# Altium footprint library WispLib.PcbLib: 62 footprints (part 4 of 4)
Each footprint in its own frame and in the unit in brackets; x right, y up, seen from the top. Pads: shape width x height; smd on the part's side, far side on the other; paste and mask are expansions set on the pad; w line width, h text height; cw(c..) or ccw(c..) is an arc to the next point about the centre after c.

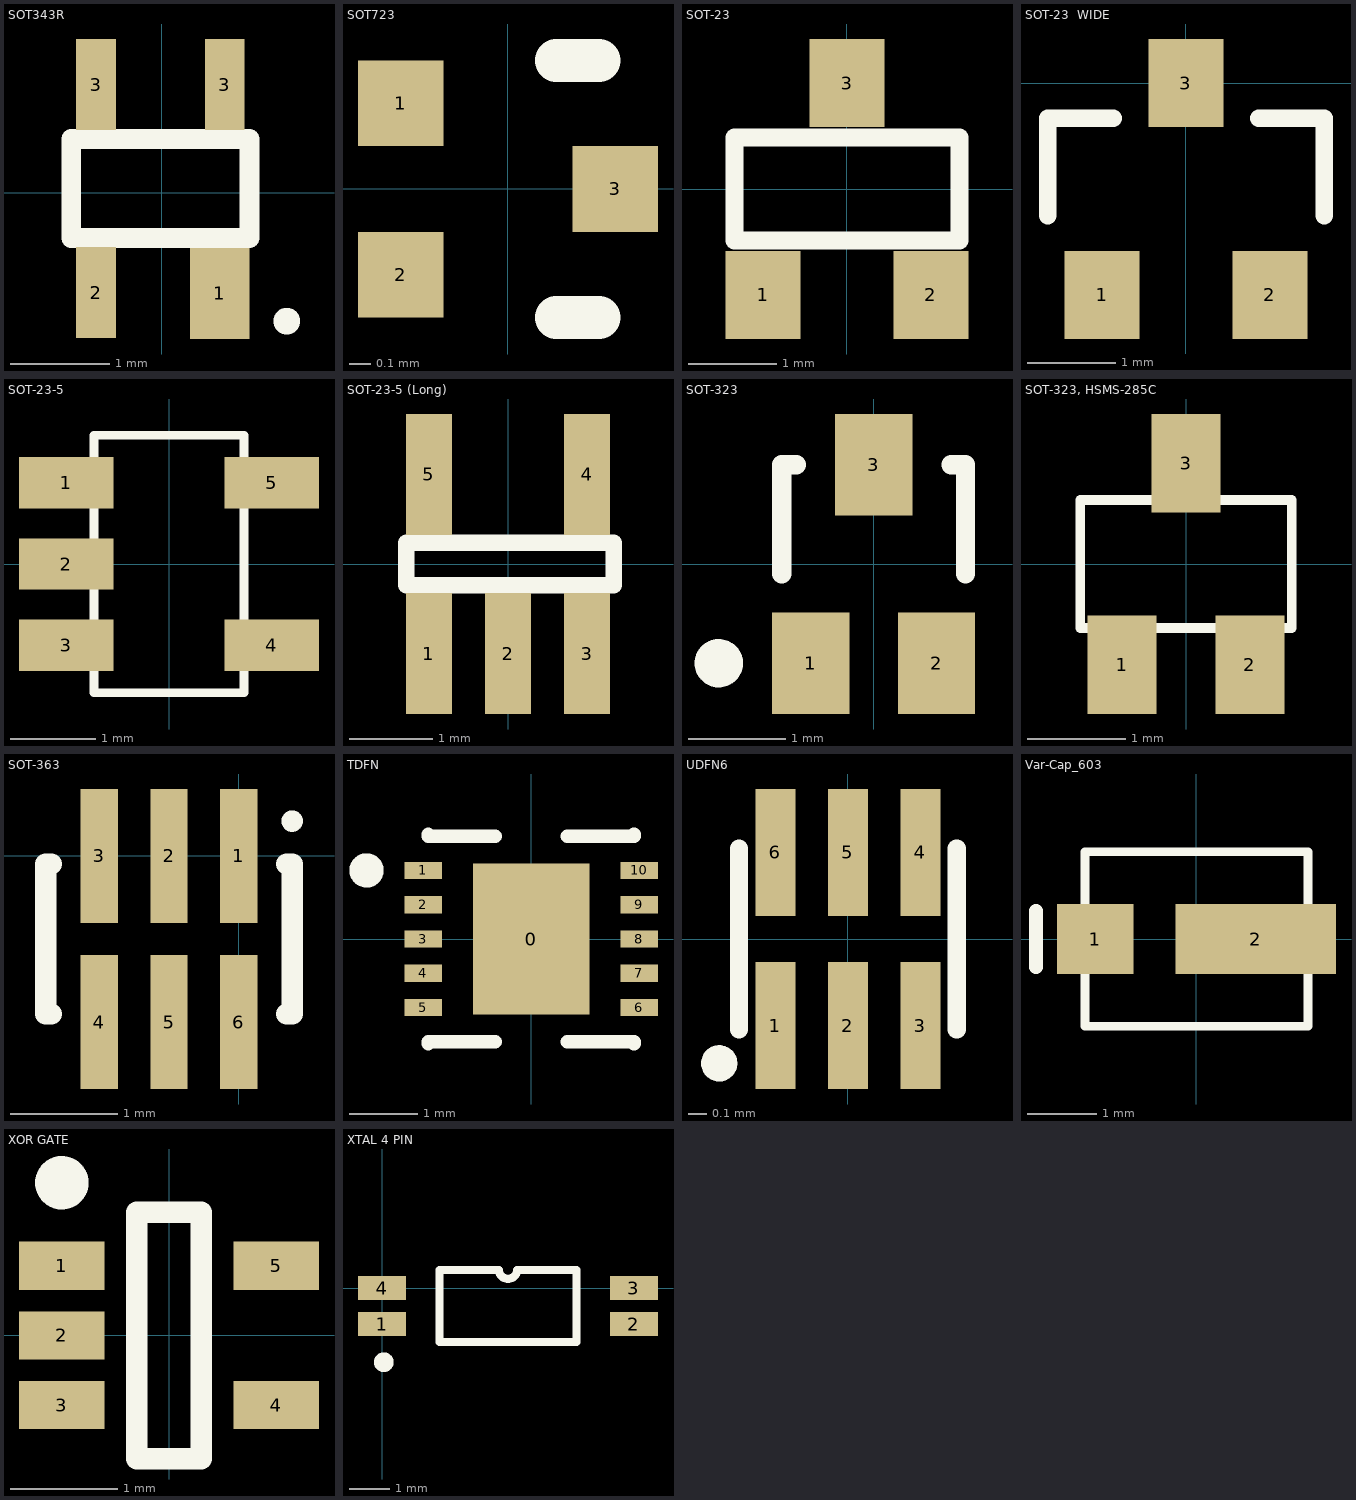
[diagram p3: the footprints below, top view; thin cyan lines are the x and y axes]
## SOT343R [mm] "SOT343R Package for BF1212"
pads (4):
  rect 0.6x0.92 smd: 1(0.584,-1.016)
  rect 0.4x0.92 smd: 2(-0.664,-1.007) 3(-0.664,1.093) 3(0.636,1.093)
Top Overlay:
  circle w0.254: c1.262,-1.295 r0.008
  lines w0.2: -0.914,-0.457 0.886,-0.457 0.886,0.543 -0.914,0.543 -0.914,-0.457

## SOT723 [mm] "SOT723, 3-Leads, Body 1.3x1.3mm (max), Pitch 0.40mm, IPC Medium Density"
height 0.55
pads (3):
  rect 0.4x0.4 smd: 1(-0.5,0.4) 2(-0.5,-0.4) 3(0.5,0)
Top Overlay:
  lines w0.2: 0.225,-0.6 0.425,-0.6 ; 0.225,0.6 0.425,0.6

## SOT-23 [mm] "SOT-23; 3 Leads; Body 3.0 x 2.5 mm, inc. leads (LxW max)"
pads (3):
  rect 0.85x1 smd: 1(-0.95,-1.2) 2(0.95,-1.2) 3(0,1.2)
Top Overlay:
  lines w0.2: -1.275,-0.584 -1.275,0.584 1.275,0.584 1.275,-0.584 -1.275,-0.584

## SOT-23  WIDE [mm] "SOT-23  WIDE"
height 0.127
pads (3):
  rect 0.85x1 smd: 1(-0.95,-2.4) 2(0.95,-2.4) 3(0,0)
Top Overlay:
  lines w0.2: -1.565,-1.5 -1.565,-0.4 -0.825,-0.4 ; 0.825,-0.4 1.565,-0.4 1.565,-1.5

## SOT-23-5 [mm] "SOT23, 5-Leads, Body 3.0x3.0mm (max), Pitch 0.95mm, IPC Medium Density"
height 1.45
pads (5):
  rect 1.1x0.6 smd: 1(-1.2,0.95) 2(-1.2,0) 3(-1.2,-0.95) 4(1.2,-0.95) 5(1.2,0.95)
Top Overlay:
  lines w0.1: -0.875,-1.5 -0.875,1.5 0.875,1.5 0.875,-1.5 -0.875,-1.5

## SOT-23-5 (Long) [mm] "SOT-23/SC-74A; 5 Leads; Body 3 x 3.1 mm, inc. leads (LxW max)"
height 1.45
pads (5):
  rect 0.55x1.45 smd: 1(-0.95,-1.075) 2(0,-1.075) 3(0.95,-1.075) 4(0.95,1.075) 5(-0.95,1.075)
Top Overlay:
  lines w0.2: -1.219,-0.254 -1.219,0.254 1.27,0.254 1.27,-0.254 -1.219,-0.254

## SOT-323 [mm] "SOT-323/SC-70; 3 Leads; Body 2.2 x 2.2 mm, inc. leads (LxW max)"
height 1
pads (3):
  rect 0.8x1.05 smd: 1(-0.65,-1.025) 2(0.65,-1.025) 3(0,1.025)
Top Overlay:
  circle w0.25: c-1.6,-1.025 r0.125
  lines w0.2: -0.95,-0.1 -0.95,1.025 -0.8,1.025 ; 0.8,1.025 0.95,1.025 0.95,-0.1

## SOT-323, HSMS-285C [mm] "SOT-323/SC-70; 3 Leads; HSMS-285C"
height 1
pads (3):
  rect 0.7x1 smd: 1(-0.65,-1.025) 2(0.65,-1.025) 3(0,1.025)
Top Overlay:
  lines w0.1: -1.075,-0.65 1.075,-0.65 1.075,0.65 -1.075,0.65 -1.075,-0.65

## SOT-363 [mm] "SOT-363 ,SC-88 ,6 Lead"
pads (6):
  rect 0.35x1.25 smd: 1(0,0) 2(-0.65,0) 3(-1.3,0) 4(-1.3,-1.55) 5(-0.65,-1.55) 6(0,-1.55)
Top Overlay:
  circle w0.1: c0.5,0.325 r0.05
  lines w0.2: -1.75,-1.475 -1.8,-1.475 -1.8,-0.075 -1.75,-0.075 ; 0.45,-1.475 0.5,-1.475 0.5,-0.075 0.45,-0.075

## TDFN [mm] "TDFN, 10-Leads, Body 3.0x3.0mm (max), Pitch 0.50mm, IPC Medium Density"
height 0.8
pads (11):
  rect 1.7x2.2 smd: 0(0,0)
  rect 0.55x0.25 smd: 1(-1.575,1) 2(-1.575,0.5) 3(-1.575,0) 4(-1.575,-0.5) 5(-1.575,-1) 6(1.575,-1) 7(1.575,-0.5) 8(1.575,0) 9(1.575,0.5) 10(1.575,1)
Top Overlay:
  circle w0.25: c-2.4,1 r0.125
  lines w0.2: -1.5,-1.525 -1.5,-1.5 -0.525,-1.5 ; -1.5,1.525 -1.5,1.5 -0.525,1.5 ; 0.525,-1.5 1.5,-1.5 1.5,-1.525 ; 0.525,1.5 1.5,1.5 1.5,1.525

## UDFN6 [mm] "UDFN6 - Level Shifter -  NLSV1T244"
height 0.5
pads (6):
  rect 0.22x0.7 smd: 1(-0.4,-0.477) 2(0,-0.477) 3(0.4,-0.477) 4(0.4,0.477) 5(0,0.477) 6(-0.4,0.477)
Top Overlay:
  circle w0.1: c-0.71,-0.686 r0.05
  lines w0.1: -0.6,-0.5 -0.6,0.5 ; 0.6,-0.5 0.6,0.5

## Var-Cap_603 [mm] "Var-Cap 603 Compatible, DK: 490-2009 & SG2026CT"
height 1.3
pads (2):
  rect 1.1x1 smd: 1(-1.45,0)
  rect 2.3x1 smd: 2(0.85,0)
Top Overlay:
  lines w0.127: -1.6,-1.25 -1.6,1.25 1.6,1.25 1.6,-1.25 -1.6,-1.25
  lines w0.2: -2.3,-0.4 -2.3,0.4

## XOR GATE [mm] "SOT23, 5-Leads, Body 2.05x2.13mm, Pitch 0.65mm, IPC Medium Density"
height 1.1
pads (5):
  rect 0.8x0.45 smd: 1(-1,0.65) 2(-1,0) 3(-1,-0.65) 4(1,-0.65) 5(1,0.65)
Top Overlay:
  circle w0.25: c-1,1.425 r0.125
  lines w0.2: -0.3,-1.15 -0.3,1.15 0.3,1.15 0.3,-1.15 -0.3,-1.15
3D body: height 1.1, standoff 0, extent -0.675,-1.125 0.675,1.125

## XTAL 4 PIN [mm]
pads (4):
  rect 1.2x0.6 smd: 1(0,-0.9) 2(6.3,-0.9) 3(6.3,0) 4(0,0)
Top Overlay:
  circle w0.254: c0.045,-1.854 r0.12
  lines w0.2: 1.435,-1.35 4.865,-1.35 4.865,0.45 3.375,0.45 cw(c3.15,0.45) 2.925,0.45 1.435,0.45 1.435,-1.35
